VERSION 5.7 ;
  NOWIREEXTENSIONATPIN ON ;
  DIVIDERCHAR "/" ;
  BUSBITCHARS "[]" ;
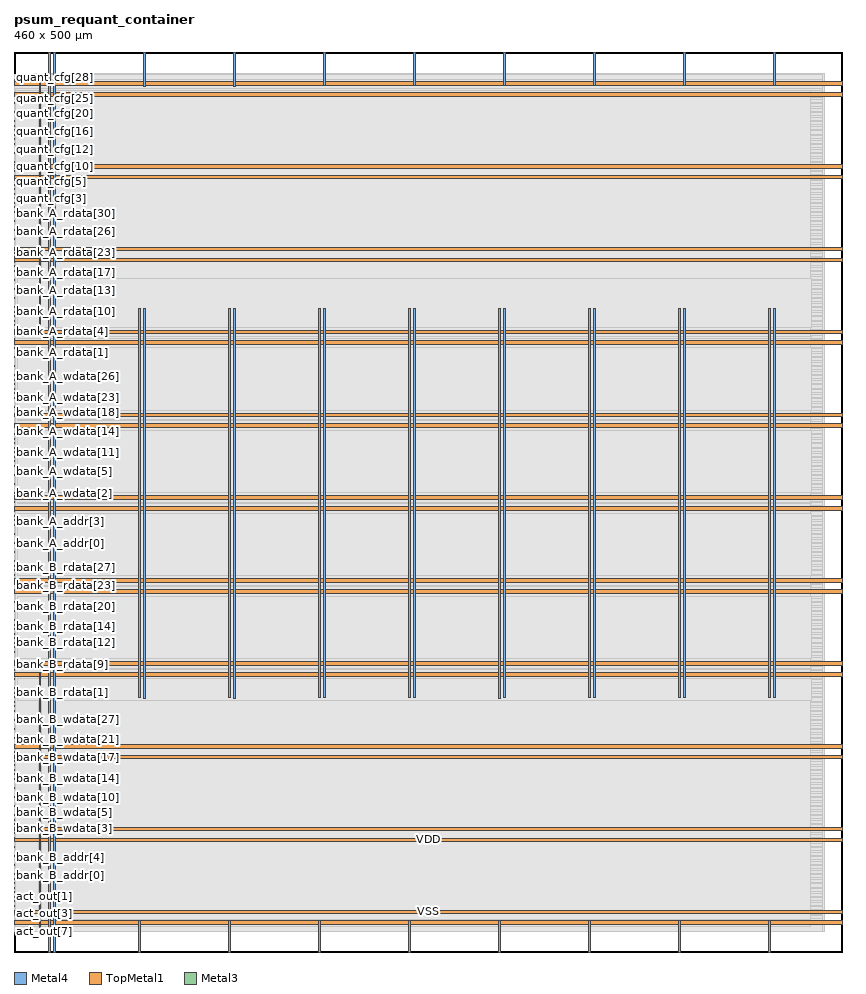
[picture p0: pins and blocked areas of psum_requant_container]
MACRO psum_requant_container
  CLASS BLOCK ;
  FOREIGN psum_requant_container ;
  ORIGIN 0.000 0.000 ;
  SIZE 460.000 BY 500.000 ;
  PIN VDD
    DIRECTION INOUT ;
    USE POWER ;
    PORT
      LAYER Metal4 ;
        RECT 19.100 0.000 20.100 500.000 ;
    END
    PORT
      LAYER Metal4 ;
        RECT 69.100 0.000 70.100 17.520 ;
    END
    PORT
      LAYER Metal4 ;
        RECT 69.100 141.260 70.100 357.520 ;
    END
    PORT
      LAYER Metal4 ;
        RECT 119.100 0.000 120.100 17.520 ;
    END
    PORT
      LAYER Metal4 ;
        RECT 119.100 141.260 120.100 357.520 ;
    END
    PORT
      LAYER Metal4 ;
        RECT 169.100 0.000 170.100 17.520 ;
    END
    PORT
      LAYER Metal4 ;
        RECT 169.100 141.260 170.100 357.520 ;
    END
    PORT
      LAYER Metal4 ;
        RECT 219.100 0.000 220.100 17.520 ;
    END
    PORT
      LAYER Metal4 ;
        RECT 219.100 141.260 220.100 357.520 ;
    END
    PORT
      LAYER Metal4 ;
        RECT 269.100 0.000 270.100 17.760 ;
    END
    PORT
      LAYER Metal4 ;
        RECT 269.100 141.020 270.100 357.760 ;
    END
    PORT
      LAYER Metal4 ;
        RECT 319.100 0.000 320.100 17.520 ;
    END
    PORT
      LAYER Metal4 ;
        RECT 319.100 141.260 320.100 357.520 ;
    END
    PORT
      LAYER Metal4 ;
        RECT 369.100 0.000 370.100 17.520 ;
    END
    PORT
      LAYER Metal4 ;
        RECT 369.100 141.260 370.100 357.520 ;
    END
    PORT
      LAYER Metal4 ;
        RECT 419.100 0.000 420.100 17.520 ;
    END
    PORT
      LAYER Metal4 ;
        RECT 419.100 141.260 420.100 357.520 ;
    END
    PORT
      LAYER TopMetal1 ;
        RECT 0.000 15.240 460.000 17.240 ;
    END
    PORT
      LAYER TopMetal1 ;
        RECT 0.000 61.270 460.000 63.270 ;
    END
    PORT
      LAYER TopMetal1 ;
        RECT 0.000 107.300 460.000 109.300 ;
    END
    PORT
      LAYER TopMetal1 ;
        RECT 0.000 153.330 460.000 155.330 ;
    END
    PORT
      LAYER TopMetal1 ;
        RECT 0.000 199.360 460.000 201.360 ;
    END
    PORT
      LAYER TopMetal1 ;
        RECT 0.000 245.390 460.000 247.390 ;
    END
    PORT
      LAYER TopMetal1 ;
        RECT 0.000 291.420 460.000 293.420 ;
    END
    PORT
      LAYER TopMetal1 ;
        RECT 0.000 337.450 460.000 339.450 ;
    END
    PORT
      LAYER TopMetal1 ;
        RECT 0.000 383.480 460.000 385.480 ;
    END
    PORT
      LAYER TopMetal1 ;
        RECT 0.000 429.510 460.000 431.510 ;
    END
    PORT
      LAYER TopMetal1 ;
        RECT 0.000 475.540 460.000 477.540 ;
    END
  END VDD
  PIN VSS
    DIRECTION INOUT ;
    USE GROUND ;
    PORT
      LAYER Metal4 ;
        RECT 22.100 0.000 23.100 500.000 ;
    END
    PORT
      LAYER Metal4 ;
        RECT 72.100 141.020 73.100 357.760 ;
    END
    PORT
      LAYER Metal4 ;
        RECT 72.100 481.020 73.100 500.000 ;
    END
    PORT
      LAYER Metal4 ;
        RECT 122.100 141.020 123.100 357.760 ;
    END
    PORT
      LAYER Metal4 ;
        RECT 122.100 481.020 123.100 500.000 ;
    END
    PORT
      LAYER Metal4 ;
        RECT 172.100 141.260 173.100 357.520 ;
    END
    PORT
      LAYER Metal4 ;
        RECT 172.100 481.260 173.100 500.000 ;
    END
    PORT
      LAYER Metal4 ;
        RECT 222.100 141.260 223.100 357.520 ;
    END
    PORT
      LAYER Metal4 ;
        RECT 222.100 481.260 223.100 500.000 ;
    END
    PORT
      LAYER Metal4 ;
        RECT 272.100 141.260 273.100 357.520 ;
    END
    PORT
      LAYER Metal4 ;
        RECT 272.100 481.260 273.100 500.000 ;
    END
    PORT
      LAYER Metal4 ;
        RECT 322.100 141.260 323.100 357.520 ;
    END
    PORT
      LAYER Metal4 ;
        RECT 322.100 481.260 323.100 500.000 ;
    END
    PORT
      LAYER Metal4 ;
        RECT 372.100 141.260 373.100 357.520 ;
    END
    PORT
      LAYER Metal4 ;
        RECT 372.100 481.260 373.100 500.000 ;
    END
    PORT
      LAYER Metal4 ;
        RECT 422.100 141.260 423.100 357.520 ;
    END
    PORT
      LAYER Metal4 ;
        RECT 422.100 481.260 423.100 500.000 ;
    END
    PORT
      LAYER TopMetal1 ;
        RECT 0.000 21.240 460.000 23.240 ;
    END
    PORT
      LAYER TopMetal1 ;
        RECT 0.000 67.270 460.000 69.270 ;
    END
    PORT
      LAYER TopMetal1 ;
        RECT 0.000 113.300 460.000 115.300 ;
    END
    PORT
      LAYER TopMetal1 ;
        RECT 0.000 159.330 460.000 161.330 ;
    END
    PORT
      LAYER TopMetal1 ;
        RECT 0.000 205.360 460.000 207.360 ;
    END
    PORT
      LAYER TopMetal1 ;
        RECT 0.000 251.390 460.000 253.390 ;
    END
    PORT
      LAYER TopMetal1 ;
        RECT 0.000 297.420 460.000 299.420 ;
    END
    PORT
      LAYER TopMetal1 ;
        RECT 0.000 343.450 460.000 345.450 ;
    END
    PORT
      LAYER TopMetal1 ;
        RECT 0.000 389.480 460.000 391.480 ;
    END
    PORT
      LAYER TopMetal1 ;
        RECT 0.000 435.510 460.000 437.510 ;
    END
    PORT
      LAYER TopMetal1 ;
        RECT 0.000 481.540 460.000 483.540 ;
    END
    PORT
      LAYER Metal4 ;
        RECT 13.900 11.120 14.900 155.200 ;
    END
    PORT
      LAYER Metal4 ;
        RECT 13.900 343.760 14.900 487.840 ;
    END
  END VSS
  PIN act_out[0]
    DIRECTION OUTPUT ;
    USE SIGNAL ;
    ANTENNADIFFAREA 0.708600 ;
    PORT
      LAYER Metal3 ;
        RECT 0.000 32.980 0.400 33.380 ;
    END
  END act_out[0]
  PIN act_out[1]
    DIRECTION OUTPUT ;
    USE SIGNAL ;
    ANTENNADIFFAREA 0.708600 ;
    PORT
      LAYER Metal3 ;
        RECT 0.000 30.460 0.400 30.860 ;
    END
  END act_out[1]
  PIN act_out[2]
    DIRECTION OUTPUT ;
    USE SIGNAL ;
    ANTENNADIFFAREA 0.708600 ;
    PORT
      LAYER Metal3 ;
        RECT 0.000 27.940 0.400 28.340 ;
    END
  END act_out[2]
  PIN act_out[3]
    DIRECTION OUTPUT ;
    USE SIGNAL ;
    ANTENNADIFFAREA 0.708600 ;
    PORT
      LAYER Metal3 ;
        RECT 0.000 25.420 0.400 25.820 ;
    END
  END act_out[3]
  PIN act_out[4]
    DIRECTION OUTPUT ;
    USE SIGNAL ;
    ANTENNADIFFAREA 0.708600 ;
    PORT
      LAYER Metal3 ;
        RECT 0.000 22.900 0.400 23.300 ;
    END
  END act_out[4]
  PIN act_out[5]
    DIRECTION OUTPUT ;
    USE SIGNAL ;
    ANTENNADIFFAREA 0.708600 ;
    PORT
      LAYER Metal3 ;
        RECT 0.000 20.380 0.400 20.780 ;
    END
  END act_out[5]
  PIN act_out[6]
    DIRECTION OUTPUT ;
    USE SIGNAL ;
    ANTENNADIFFAREA 0.708600 ;
    PORT
      LAYER Metal3 ;
        RECT 0.000 17.860 0.400 18.260 ;
    END
  END act_out[6]
  PIN act_out[7]
    DIRECTION OUTPUT ;
    USE SIGNAL ;
    ANTENNADIFFAREA 0.708600 ;
    PORT
      LAYER Metal3 ;
        RECT 0.000 15.340 0.400 15.740 ;
    END
  END act_out[7]
  PIN bank_A_addr[0]
    DIRECTION INPUT ;
    USE SIGNAL ;
    ANTENNAGATEAREA 0.180700 ;
    PORT
      LAYER Metal3 ;
        RECT 0.000 227.020 0.400 227.420 ;
    END
  END bank_A_addr[0]
  PIN bank_A_addr[1]
    DIRECTION INPUT ;
    USE SIGNAL ;
    ANTENNAGATEAREA 0.180700 ;
    PORT
      LAYER Metal3 ;
        RECT 0.000 229.540 0.400 229.940 ;
    END
  END bank_A_addr[1]
  PIN bank_A_addr[2]
    DIRECTION INPUT ;
    USE SIGNAL ;
    ANTENNAGATEAREA 0.180700 ;
    PORT
      LAYER Metal3 ;
        RECT 0.000 232.060 0.400 232.460 ;
    END
  END bank_A_addr[2]
  PIN bank_A_addr[3]
    DIRECTION INPUT ;
    USE SIGNAL ;
    ANTENNAGATEAREA 0.180700 ;
    PORT
      LAYER Metal3 ;
        RECT 0.000 234.580 0.400 234.980 ;
    END
  END bank_A_addr[3]
  PIN bank_A_addr[4]
    DIRECTION INPUT ;
    USE SIGNAL ;
    ANTENNAGATEAREA 0.180700 ;
    PORT
      LAYER Metal3 ;
        RECT 0.000 237.100 0.400 237.500 ;
    END
  END bank_A_addr[4]
  PIN bank_A_addr[5]
    DIRECTION INPUT ;
    USE SIGNAL ;
    ANTENNAGATEAREA 0.180700 ;
    PORT
      LAYER Metal3 ;
        RECT 0.000 239.620 0.400 240.020 ;
    END
  END bank_A_addr[5]
  PIN bank_A_addr[6]
    DIRECTION INPUT ;
    USE SIGNAL ;
    ANTENNAGATEAREA 0.180700 ;
    PORT
      LAYER Metal3 ;
        RECT 0.000 242.140 0.400 242.540 ;
    END
  END bank_A_addr[6]
  PIN bank_A_addr[7]
    DIRECTION INPUT ;
    USE SIGNAL ;
    ANTENNAGATEAREA 0.180700 ;
    PORT
      LAYER Metal3 ;
        RECT 0.000 244.660 0.400 245.060 ;
    END
  END bank_A_addr[7]
  PIN bank_A_rdata[0]
    DIRECTION OUTPUT ;
    USE SIGNAL ;
    ANTENNADIFFAREA 0.708600 ;
    PORT
      LAYER Metal3 ;
        RECT 0.000 330.340 0.400 330.740 ;
    END
  END bank_A_rdata[0]
  PIN bank_A_rdata[10]
    DIRECTION OUTPUT ;
    USE SIGNAL ;
    ANTENNADIFFAREA 0.708600 ;
    PORT
      LAYER Metal3 ;
        RECT 0.000 355.540 0.400 355.940 ;
    END
  END bank_A_rdata[10]
  PIN bank_A_rdata[11]
    DIRECTION OUTPUT ;
    USE SIGNAL ;
    ANTENNADIFFAREA 0.708600 ;
    PORT
      LAYER Metal3 ;
        RECT 0.000 358.060 0.400 358.460 ;
    END
  END bank_A_rdata[11]
  PIN bank_A_rdata[12]
    DIRECTION OUTPUT ;
    USE SIGNAL ;
    ANTENNADIFFAREA 0.708600 ;
    PORT
      LAYER Metal3 ;
        RECT 0.000 360.580 0.400 360.980 ;
    END
  END bank_A_rdata[12]
  PIN bank_A_rdata[13]
    DIRECTION OUTPUT ;
    USE SIGNAL ;
    ANTENNADIFFAREA 0.708600 ;
    PORT
      LAYER Metal3 ;
        RECT 0.000 363.100 0.400 363.500 ;
    END
  END bank_A_rdata[13]
  PIN bank_A_rdata[14]
    DIRECTION OUTPUT ;
    USE SIGNAL ;
    ANTENNADIFFAREA 0.708600 ;
    PORT
      LAYER Metal3 ;
        RECT 0.000 365.620 0.400 366.020 ;
    END
  END bank_A_rdata[14]
  PIN bank_A_rdata[15]
    DIRECTION OUTPUT ;
    USE SIGNAL ;
    ANTENNADIFFAREA 0.708600 ;
    PORT
      LAYER Metal3 ;
        RECT 0.000 368.140 0.400 368.540 ;
    END
  END bank_A_rdata[15]
  PIN bank_A_rdata[16]
    DIRECTION OUTPUT ;
    USE SIGNAL ;
    ANTENNADIFFAREA 0.708600 ;
    PORT
      LAYER Metal3 ;
        RECT 0.000 370.660 0.400 371.060 ;
    END
  END bank_A_rdata[16]
  PIN bank_A_rdata[17]
    DIRECTION OUTPUT ;
    USE SIGNAL ;
    ANTENNADIFFAREA 0.708600 ;
    PORT
      LAYER Metal3 ;
        RECT 0.000 373.180 0.400 373.580 ;
    END
  END bank_A_rdata[17]
  PIN bank_A_rdata[18]
    DIRECTION OUTPUT ;
    USE SIGNAL ;
    ANTENNADIFFAREA 0.708600 ;
    PORT
      LAYER Metal3 ;
        RECT 0.000 375.700 0.400 376.100 ;
    END
  END bank_A_rdata[18]
  PIN bank_A_rdata[19]
    DIRECTION OUTPUT ;
    USE SIGNAL ;
    ANTENNADIFFAREA 0.708600 ;
    PORT
      LAYER Metal3 ;
        RECT 0.000 378.220 0.400 378.620 ;
    END
  END bank_A_rdata[19]
  PIN bank_A_rdata[1]
    DIRECTION OUTPUT ;
    USE SIGNAL ;
    ANTENNADIFFAREA 0.708600 ;
    PORT
      LAYER Metal3 ;
        RECT 0.000 332.860 0.400 333.260 ;
    END
  END bank_A_rdata[1]
  PIN bank_A_rdata[20]
    DIRECTION OUTPUT ;
    USE SIGNAL ;
    ANTENNADIFFAREA 0.708600 ;
    PORT
      LAYER Metal3 ;
        RECT 0.000 380.740 0.400 381.140 ;
    END
  END bank_A_rdata[20]
  PIN bank_A_rdata[21]
    DIRECTION OUTPUT ;
    USE SIGNAL ;
    ANTENNADIFFAREA 0.708600 ;
    PORT
      LAYER Metal3 ;
        RECT 0.000 383.260 0.400 383.660 ;
    END
  END bank_A_rdata[21]
  PIN bank_A_rdata[22]
    DIRECTION OUTPUT ;
    USE SIGNAL ;
    ANTENNADIFFAREA 0.708600 ;
    PORT
      LAYER Metal3 ;
        RECT 0.000 385.780 0.400 386.180 ;
    END
  END bank_A_rdata[22]
  PIN bank_A_rdata[23]
    DIRECTION OUTPUT ;
    USE SIGNAL ;
    ANTENNADIFFAREA 0.708600 ;
    PORT
      LAYER Metal3 ;
        RECT 0.000 388.300 0.400 388.700 ;
    END
  END bank_A_rdata[23]
  PIN bank_A_rdata[24]
    DIRECTION OUTPUT ;
    USE SIGNAL ;
    ANTENNADIFFAREA 0.708600 ;
    PORT
      LAYER Metal3 ;
        RECT 0.000 390.820 0.400 391.220 ;
    END
  END bank_A_rdata[24]
  PIN bank_A_rdata[25]
    DIRECTION OUTPUT ;
    USE SIGNAL ;
    ANTENNADIFFAREA 0.708600 ;
    PORT
      LAYER Metal3 ;
        RECT 0.000 393.340 0.400 393.740 ;
    END
  END bank_A_rdata[25]
  PIN bank_A_rdata[26]
    DIRECTION OUTPUT ;
    USE SIGNAL ;
    ANTENNADIFFAREA 0.708600 ;
    PORT
      LAYER Metal3 ;
        RECT 0.000 395.860 0.400 396.260 ;
    END
  END bank_A_rdata[26]
  PIN bank_A_rdata[27]
    DIRECTION OUTPUT ;
    USE SIGNAL ;
    ANTENNADIFFAREA 0.708600 ;
    PORT
      LAYER Metal3 ;
        RECT 0.000 398.380 0.400 398.780 ;
    END
  END bank_A_rdata[27]
  PIN bank_A_rdata[28]
    DIRECTION OUTPUT ;
    USE SIGNAL ;
    ANTENNADIFFAREA 0.708600 ;
    PORT
      LAYER Metal3 ;
        RECT 0.000 400.900 0.400 401.300 ;
    END
  END bank_A_rdata[28]
  PIN bank_A_rdata[29]
    DIRECTION OUTPUT ;
    USE SIGNAL ;
    ANTENNADIFFAREA 0.708600 ;
    PORT
      LAYER Metal3 ;
        RECT 0.000 403.420 0.400 403.820 ;
    END
  END bank_A_rdata[29]
  PIN bank_A_rdata[2]
    DIRECTION OUTPUT ;
    USE SIGNAL ;
    ANTENNADIFFAREA 0.708600 ;
    PORT
      LAYER Metal3 ;
        RECT 0.000 335.380 0.400 335.780 ;
    END
  END bank_A_rdata[2]
  PIN bank_A_rdata[30]
    DIRECTION OUTPUT ;
    USE SIGNAL ;
    ANTENNADIFFAREA 0.708600 ;
    PORT
      LAYER Metal3 ;
        RECT 0.000 405.940 0.400 406.340 ;
    END
  END bank_A_rdata[30]
  PIN bank_A_rdata[31]
    DIRECTION OUTPUT ;
    USE SIGNAL ;
    ANTENNADIFFAREA 0.708600 ;
    PORT
      LAYER Metal3 ;
        RECT 0.000 408.460 0.400 408.860 ;
    END
  END bank_A_rdata[31]
  PIN bank_A_rdata[3]
    DIRECTION OUTPUT ;
    USE SIGNAL ;
    ANTENNADIFFAREA 0.708600 ;
    PORT
      LAYER Metal3 ;
        RECT 0.000 337.900 0.400 338.300 ;
    END
  END bank_A_rdata[3]
  PIN bank_A_rdata[4]
    DIRECTION OUTPUT ;
    USE SIGNAL ;
    ANTENNADIFFAREA 0.708600 ;
    PORT
      LAYER Metal3 ;
        RECT 0.000 340.420 0.400 340.820 ;
    END
  END bank_A_rdata[4]
  PIN bank_A_rdata[5]
    DIRECTION OUTPUT ;
    USE SIGNAL ;
    ANTENNADIFFAREA 0.708600 ;
    PORT
      LAYER Metal3 ;
        RECT 0.000 342.940 0.400 343.340 ;
    END
  END bank_A_rdata[5]
  PIN bank_A_rdata[6]
    DIRECTION OUTPUT ;
    USE SIGNAL ;
    ANTENNADIFFAREA 0.708600 ;
    PORT
      LAYER Metal3 ;
        RECT 0.000 345.460 0.400 345.860 ;
    END
  END bank_A_rdata[6]
  PIN bank_A_rdata[7]
    DIRECTION OUTPUT ;
    USE SIGNAL ;
    ANTENNADIFFAREA 0.708600 ;
    PORT
      LAYER Metal3 ;
        RECT 0.000 347.980 0.400 348.380 ;
    END
  END bank_A_rdata[7]
  PIN bank_A_rdata[8]
    DIRECTION OUTPUT ;
    USE SIGNAL ;
    ANTENNADIFFAREA 0.708600 ;
    PORT
      LAYER Metal3 ;
        RECT 0.000 350.500 0.400 350.900 ;
    END
  END bank_A_rdata[8]
  PIN bank_A_rdata[9]
    DIRECTION OUTPUT ;
    USE SIGNAL ;
    ANTENNADIFFAREA 0.708600 ;
    PORT
      LAYER Metal3 ;
        RECT 0.000 353.020 0.400 353.420 ;
    END
  END bank_A_rdata[9]
  PIN bank_A_wdata[0]
    DIRECTION INPUT ;
    USE SIGNAL ;
    ANTENNAGATEAREA 0.180700 ;
    PORT
      LAYER Metal3 ;
        RECT 0.000 249.700 0.400 250.100 ;
    END
  END bank_A_wdata[0]
  PIN bank_A_wdata[10]
    DIRECTION INPUT ;
    USE SIGNAL ;
    ANTENNAGATEAREA 0.180700 ;
    PORT
      LAYER Metal3 ;
        RECT 0.000 274.900 0.400 275.300 ;
    END
  END bank_A_wdata[10]
  PIN bank_A_wdata[11]
    DIRECTION INPUT ;
    USE SIGNAL ;
    ANTENNAGATEAREA 0.180700 ;
    PORT
      LAYER Metal3 ;
        RECT 0.000 277.420 0.400 277.820 ;
    END
  END bank_A_wdata[11]
  PIN bank_A_wdata[12]
    DIRECTION INPUT ;
    USE SIGNAL ;
    ANTENNAGATEAREA 0.180700 ;
    PORT
      LAYER Metal3 ;
        RECT 0.000 279.940 0.400 280.340 ;
    END
  END bank_A_wdata[12]
  PIN bank_A_wdata[13]
    DIRECTION INPUT ;
    USE SIGNAL ;
    ANTENNAGATEAREA 0.180700 ;
    PORT
      LAYER Metal3 ;
        RECT 0.000 282.460 0.400 282.860 ;
    END
  END bank_A_wdata[13]
  PIN bank_A_wdata[14]
    DIRECTION INPUT ;
    USE SIGNAL ;
    ANTENNAGATEAREA 0.180700 ;
    PORT
      LAYER Metal3 ;
        RECT 0.000 284.980 0.400 285.380 ;
    END
  END bank_A_wdata[14]
  PIN bank_A_wdata[15]
    DIRECTION INPUT ;
    USE SIGNAL ;
    ANTENNAGATEAREA 0.180700 ;
    PORT
      LAYER Metal3 ;
        RECT 0.000 287.500 0.400 287.900 ;
    END
  END bank_A_wdata[15]
  PIN bank_A_wdata[16]
    DIRECTION INPUT ;
    USE SIGNAL ;
    ANTENNAGATEAREA 0.180700 ;
    PORT
      LAYER Metal3 ;
        RECT 0.000 290.020 0.400 290.420 ;
    END
  END bank_A_wdata[16]
  PIN bank_A_wdata[17]
    DIRECTION INPUT ;
    USE SIGNAL ;
    ANTENNAGATEAREA 0.180700 ;
    PORT
      LAYER Metal3 ;
        RECT 0.000 292.540 0.400 292.940 ;
    END
  END bank_A_wdata[17]
  PIN bank_A_wdata[18]
    DIRECTION INPUT ;
    USE SIGNAL ;
    ANTENNAGATEAREA 0.180700 ;
    PORT
      LAYER Metal3 ;
        RECT 0.000 295.060 0.400 295.460 ;
    END
  END bank_A_wdata[18]
  PIN bank_A_wdata[19]
    DIRECTION INPUT ;
    USE SIGNAL ;
    ANTENNAGATEAREA 0.180700 ;
    PORT
      LAYER Metal3 ;
        RECT 0.000 297.580 0.400 297.980 ;
    END
  END bank_A_wdata[19]
  PIN bank_A_wdata[1]
    DIRECTION INPUT ;
    USE SIGNAL ;
    ANTENNAGATEAREA 0.180700 ;
    PORT
      LAYER Metal3 ;
        RECT 0.000 252.220 0.400 252.620 ;
    END
  END bank_A_wdata[1]
  PIN bank_A_wdata[20]
    DIRECTION INPUT ;
    USE SIGNAL ;
    ANTENNAGATEAREA 0.180700 ;
    PORT
      LAYER Metal3 ;
        RECT 0.000 300.100 0.400 300.500 ;
    END
  END bank_A_wdata[20]
  PIN bank_A_wdata[21]
    DIRECTION INPUT ;
    USE SIGNAL ;
    ANTENNAGATEAREA 0.180700 ;
    PORT
      LAYER Metal3 ;
        RECT 0.000 302.620 0.400 303.020 ;
    END
  END bank_A_wdata[21]
  PIN bank_A_wdata[22]
    DIRECTION INPUT ;
    USE SIGNAL ;
    ANTENNAGATEAREA 0.180700 ;
    PORT
      LAYER Metal3 ;
        RECT 0.000 305.140 0.400 305.540 ;
    END
  END bank_A_wdata[22]
  PIN bank_A_wdata[23]
    DIRECTION INPUT ;
    USE SIGNAL ;
    ANTENNAGATEAREA 0.180700 ;
    PORT
      LAYER Metal3 ;
        RECT 0.000 307.660 0.400 308.060 ;
    END
  END bank_A_wdata[23]
  PIN bank_A_wdata[24]
    DIRECTION INPUT ;
    USE SIGNAL ;
    ANTENNAGATEAREA 0.180700 ;
    PORT
      LAYER Metal3 ;
        RECT 0.000 310.180 0.400 310.580 ;
    END
  END bank_A_wdata[24]
  PIN bank_A_wdata[25]
    DIRECTION INPUT ;
    USE SIGNAL ;
    ANTENNAGATEAREA 0.180700 ;
    PORT
      LAYER Metal3 ;
        RECT 0.000 312.700 0.400 313.100 ;
    END
  END bank_A_wdata[25]
  PIN bank_A_wdata[26]
    DIRECTION INPUT ;
    USE SIGNAL ;
    ANTENNAGATEAREA 0.180700 ;
    PORT
      LAYER Metal3 ;
        RECT 0.000 315.220 0.400 315.620 ;
    END
  END bank_A_wdata[26]
  PIN bank_A_wdata[27]
    DIRECTION INPUT ;
    USE SIGNAL ;
    ANTENNAGATEAREA 0.180700 ;
    PORT
      LAYER Metal3 ;
        RECT 0.000 317.740 0.400 318.140 ;
    END
  END bank_A_wdata[27]
  PIN bank_A_wdata[28]
    DIRECTION INPUT ;
    USE SIGNAL ;
    ANTENNAGATEAREA 0.180700 ;
    PORT
      LAYER Metal3 ;
        RECT 0.000 320.260 0.400 320.660 ;
    END
  END bank_A_wdata[28]
  PIN bank_A_wdata[29]
    DIRECTION INPUT ;
    USE SIGNAL ;
    ANTENNAGATEAREA 0.180700 ;
    PORT
      LAYER Metal3 ;
        RECT 0.000 322.780 0.400 323.180 ;
    END
  END bank_A_wdata[29]
  PIN bank_A_wdata[2]
    DIRECTION INPUT ;
    USE SIGNAL ;
    ANTENNAGATEAREA 0.180700 ;
    PORT
      LAYER Metal3 ;
        RECT 0.000 254.740 0.400 255.140 ;
    END
  END bank_A_wdata[2]
  PIN bank_A_wdata[30]
    DIRECTION INPUT ;
    USE SIGNAL ;
    ANTENNAGATEAREA 0.180700 ;
    PORT
      LAYER Metal3 ;
        RECT 0.000 325.300 0.400 325.700 ;
    END
  END bank_A_wdata[30]
  PIN bank_A_wdata[31]
    DIRECTION INPUT ;
    USE SIGNAL ;
    ANTENNAGATEAREA 0.180700 ;
    PORT
      LAYER Metal3 ;
        RECT 0.000 327.820 0.400 328.220 ;
    END
  END bank_A_wdata[31]
  PIN bank_A_wdata[3]
    DIRECTION INPUT ;
    USE SIGNAL ;
    ANTENNAGATEAREA 0.180700 ;
    PORT
      LAYER Metal3 ;
        RECT 0.000 257.260 0.400 257.660 ;
    END
  END bank_A_wdata[3]
  PIN bank_A_wdata[4]
    DIRECTION INPUT ;
    USE SIGNAL ;
    ANTENNAGATEAREA 0.180700 ;
    PORT
      LAYER Metal3 ;
        RECT 0.000 259.780 0.400 260.180 ;
    END
  END bank_A_wdata[4]
  PIN bank_A_wdata[5]
    DIRECTION INPUT ;
    USE SIGNAL ;
    ANTENNAGATEAREA 0.180700 ;
    PORT
      LAYER Metal3 ;
        RECT 0.000 262.300 0.400 262.700 ;
    END
  END bank_A_wdata[5]
  PIN bank_A_wdata[6]
    DIRECTION INPUT ;
    USE SIGNAL ;
    ANTENNAGATEAREA 0.180700 ;
    PORT
      LAYER Metal3 ;
        RECT 0.000 264.820 0.400 265.220 ;
    END
  END bank_A_wdata[6]
  PIN bank_A_wdata[7]
    DIRECTION INPUT ;
    USE SIGNAL ;
    ANTENNAGATEAREA 0.180700 ;
    PORT
      LAYER Metal3 ;
        RECT 0.000 267.340 0.400 267.740 ;
    END
  END bank_A_wdata[7]
  PIN bank_A_wdata[8]
    DIRECTION INPUT ;
    USE SIGNAL ;
    ANTENNAGATEAREA 0.180700 ;
    PORT
      LAYER Metal3 ;
        RECT 0.000 269.860 0.400 270.260 ;
    END
  END bank_A_wdata[8]
  PIN bank_A_wdata[9]
    DIRECTION INPUT ;
    USE SIGNAL ;
    ANTENNAGATEAREA 0.180700 ;
    PORT
      LAYER Metal3 ;
        RECT 0.000 272.380 0.400 272.780 ;
    END
  END bank_A_wdata[9]
  PIN bank_A_we
    DIRECTION INPUT ;
    USE SIGNAL ;
    ANTENNAGATEAREA 0.180700 ;
    PORT
      LAYER Metal3 ;
        RECT 0.000 247.180 0.400 247.580 ;
    END
  END bank_A_we
  PIN bank_B_addr[0]
    DIRECTION INPUT ;
    USE SIGNAL ;
    ANTENNAGATEAREA 0.180700 ;
    PORT
      LAYER Metal3 ;
        RECT 0.000 38.020 0.400 38.420 ;
    END
  END bank_B_addr[0]
  PIN bank_B_addr[1]
    DIRECTION INPUT ;
    USE SIGNAL ;
    ANTENNAGATEAREA 0.180700 ;
    PORT
      LAYER Metal3 ;
        RECT 0.000 40.540 0.400 40.940 ;
    END
  END bank_B_addr[1]
  PIN bank_B_addr[2]
    DIRECTION INPUT ;
    USE SIGNAL ;
    ANTENNAGATEAREA 0.180700 ;
    PORT
      LAYER Metal3 ;
        RECT 0.000 43.060 0.400 43.460 ;
    END
  END bank_B_addr[2]
  PIN bank_B_addr[3]
    DIRECTION INPUT ;
    USE SIGNAL ;
    ANTENNAGATEAREA 0.180700 ;
    PORT
      LAYER Metal3 ;
        RECT 0.000 45.580 0.400 45.980 ;
    END
  END bank_B_addr[3]
  PIN bank_B_addr[4]
    DIRECTION INPUT ;
    USE SIGNAL ;
    ANTENNAGATEAREA 0.180700 ;
    PORT
      LAYER Metal3 ;
        RECT 0.000 48.100 0.400 48.500 ;
    END
  END bank_B_addr[4]
  PIN bank_B_addr[5]
    DIRECTION INPUT ;
    USE SIGNAL ;
    ANTENNAGATEAREA 0.180700 ;
    PORT
      LAYER Metal3 ;
        RECT 0.000 50.620 0.400 51.020 ;
    END
  END bank_B_addr[5]
  PIN bank_B_addr[6]
    DIRECTION INPUT ;
    USE SIGNAL ;
    ANTENNAGATEAREA 0.180700 ;
    PORT
      LAYER Metal3 ;
        RECT 0.000 53.140 0.400 53.540 ;
    END
  END bank_B_addr[6]
  PIN bank_B_addr[7]
    DIRECTION INPUT ;
    USE SIGNAL ;
    ANTENNAGATEAREA 0.180700 ;
    PORT
      LAYER Metal3 ;
        RECT 0.000 55.660 0.400 56.060 ;
    END
  END bank_B_addr[7]
  PIN bank_B_rdata[0]
    DIRECTION OUTPUT ;
    USE SIGNAL ;
    ANTENNADIFFAREA 0.708600 ;
    PORT
      LAYER Metal3 ;
        RECT 0.000 141.340 0.400 141.740 ;
    END
  END bank_B_rdata[0]
  PIN bank_B_rdata[10]
    DIRECTION OUTPUT ;
    USE SIGNAL ;
    ANTENNADIFFAREA 0.708600 ;
    PORT
      LAYER Metal3 ;
        RECT 0.000 166.540 0.400 166.940 ;
    END
  END bank_B_rdata[10]
  PIN bank_B_rdata[11]
    DIRECTION OUTPUT ;
    USE SIGNAL ;
    ANTENNADIFFAREA 0.708600 ;
    PORT
      LAYER Metal3 ;
        RECT 0.000 169.060 0.400 169.460 ;
    END
  END bank_B_rdata[11]
  PIN bank_B_rdata[12]
    DIRECTION OUTPUT ;
    USE SIGNAL ;
    ANTENNADIFFAREA 0.708600 ;
    PORT
      LAYER Metal3 ;
        RECT 0.000 171.580 0.400 171.980 ;
    END
  END bank_B_rdata[12]
  PIN bank_B_rdata[13]
    DIRECTION OUTPUT ;
    USE SIGNAL ;
    ANTENNADIFFAREA 0.708600 ;
    PORT
      LAYER Metal3 ;
        RECT 0.000 174.100 0.400 174.500 ;
    END
  END bank_B_rdata[13]
  PIN bank_B_rdata[14]
    DIRECTION OUTPUT ;
    USE SIGNAL ;
    ANTENNADIFFAREA 0.708600 ;
    PORT
      LAYER Metal3 ;
        RECT 0.000 176.620 0.400 177.020 ;
    END
  END bank_B_rdata[14]
  PIN bank_B_rdata[15]
    DIRECTION OUTPUT ;
    USE SIGNAL ;
    ANTENNADIFFAREA 0.708600 ;
    PORT
      LAYER Metal3 ;
        RECT 0.000 179.140 0.400 179.540 ;
    END
  END bank_B_rdata[15]
  PIN bank_B_rdata[16]
    DIRECTION OUTPUT ;
    USE SIGNAL ;
    ANTENNADIFFAREA 0.708600 ;
    PORT
      LAYER Metal3 ;
        RECT 0.000 181.660 0.400 182.060 ;
    END
  END bank_B_rdata[16]
  PIN bank_B_rdata[17]
    DIRECTION OUTPUT ;
    USE SIGNAL ;
    ANTENNADIFFAREA 0.708600 ;
    PORT
      LAYER Metal3 ;
        RECT 0.000 184.180 0.400 184.580 ;
    END
  END bank_B_rdata[17]
  PIN bank_B_rdata[18]
    DIRECTION OUTPUT ;
    USE SIGNAL ;
    ANTENNADIFFAREA 0.708600 ;
    PORT
      LAYER Metal3 ;
        RECT 0.000 186.700 0.400 187.100 ;
    END
  END bank_B_rdata[18]
  PIN bank_B_rdata[19]
    DIRECTION OUTPUT ;
    USE SIGNAL ;
    ANTENNADIFFAREA 0.708600 ;
    PORT
      LAYER Metal3 ;
        RECT 0.000 189.220 0.400 189.620 ;
    END
  END bank_B_rdata[19]
  PIN bank_B_rdata[1]
    DIRECTION OUTPUT ;
    USE SIGNAL ;
    ANTENNADIFFAREA 0.708600 ;
    PORT
      LAYER Metal3 ;
        RECT 0.000 143.860 0.400 144.260 ;
    END
  END bank_B_rdata[1]
  PIN bank_B_rdata[20]
    DIRECTION OUTPUT ;
    USE SIGNAL ;
    ANTENNADIFFAREA 0.708600 ;
    PORT
      LAYER Metal3 ;
        RECT 0.000 191.740 0.400 192.140 ;
    END
  END bank_B_rdata[20]
  PIN bank_B_rdata[21]
    DIRECTION OUTPUT ;
    USE SIGNAL ;
    ANTENNADIFFAREA 0.708600 ;
    PORT
      LAYER Metal3 ;
        RECT 0.000 194.260 0.400 194.660 ;
    END
  END bank_B_rdata[21]
  PIN bank_B_rdata[22]
    DIRECTION OUTPUT ;
    USE SIGNAL ;
    ANTENNADIFFAREA 0.708600 ;
    PORT
      LAYER Metal3 ;
        RECT 0.000 196.780 0.400 197.180 ;
    END
  END bank_B_rdata[22]
  PIN bank_B_rdata[23]
    DIRECTION OUTPUT ;
    USE SIGNAL ;
    ANTENNADIFFAREA 0.708600 ;
    PORT
      LAYER Metal3 ;
        RECT 0.000 199.300 0.400 199.700 ;
    END
  END bank_B_rdata[23]
  PIN bank_B_rdata[24]
    DIRECTION OUTPUT ;
    USE SIGNAL ;
    ANTENNADIFFAREA 0.708600 ;
    PORT
      LAYER Metal3 ;
        RECT 0.000 201.820 0.400 202.220 ;
    END
  END bank_B_rdata[24]
  PIN bank_B_rdata[25]
    DIRECTION OUTPUT ;
    USE SIGNAL ;
    ANTENNADIFFAREA 0.708600 ;
    PORT
      LAYER Metal3 ;
        RECT 0.000 204.340 0.400 204.740 ;
    END
  END bank_B_rdata[25]
  PIN bank_B_rdata[26]
    DIRECTION OUTPUT ;
    USE SIGNAL ;
    ANTENNADIFFAREA 0.708600 ;
    PORT
      LAYER Metal3 ;
        RECT 0.000 206.860 0.400 207.260 ;
    END
  END bank_B_rdata[26]
  PIN bank_B_rdata[27]
    DIRECTION OUTPUT ;
    USE SIGNAL ;
    ANTENNADIFFAREA 0.708600 ;
    PORT
      LAYER Metal3 ;
        RECT 0.000 209.380 0.400 209.780 ;
    END
  END bank_B_rdata[27]
  PIN bank_B_rdata[28]
    DIRECTION OUTPUT ;
    USE SIGNAL ;
    ANTENNADIFFAREA 0.708600 ;
    PORT
      LAYER Metal3 ;
        RECT 0.000 211.900 0.400 212.300 ;
    END
  END bank_B_rdata[28]
  PIN bank_B_rdata[29]
    DIRECTION OUTPUT ;
    USE SIGNAL ;
    ANTENNADIFFAREA 0.708600 ;
    PORT
      LAYER Metal3 ;
        RECT 0.000 214.420 0.400 214.820 ;
    END
  END bank_B_rdata[29]
  PIN bank_B_rdata[2]
    DIRECTION OUTPUT ;
    USE SIGNAL ;
    ANTENNADIFFAREA 0.708600 ;
    PORT
      LAYER Metal3 ;
        RECT 0.000 146.380 0.400 146.780 ;
    END
  END bank_B_rdata[2]
  PIN bank_B_rdata[30]
    DIRECTION OUTPUT ;
    USE SIGNAL ;
    ANTENNADIFFAREA 0.708600 ;
    PORT
      LAYER Metal3 ;
        RECT 0.000 216.940 0.400 217.340 ;
    END
  END bank_B_rdata[30]
  PIN bank_B_rdata[31]
    DIRECTION OUTPUT ;
    USE SIGNAL ;
    ANTENNADIFFAREA 0.708600 ;
    PORT
      LAYER Metal3 ;
        RECT 0.000 219.460 0.400 219.860 ;
    END
  END bank_B_rdata[31]
  PIN bank_B_rdata[3]
    DIRECTION OUTPUT ;
    USE SIGNAL ;
    ANTENNADIFFAREA 0.708600 ;
    PORT
      LAYER Metal3 ;
        RECT 0.000 148.900 0.400 149.300 ;
    END
  END bank_B_rdata[3]
  PIN bank_B_rdata[4]
    DIRECTION OUTPUT ;
    USE SIGNAL ;
    ANTENNADIFFAREA 0.708600 ;
    PORT
      LAYER Metal3 ;
        RECT 0.000 151.420 0.400 151.820 ;
    END
  END bank_B_rdata[4]
  PIN bank_B_rdata[5]
    DIRECTION OUTPUT ;
    USE SIGNAL ;
    ANTENNADIFFAREA 0.708600 ;
    PORT
      LAYER Metal3 ;
        RECT 0.000 153.940 0.400 154.340 ;
    END
  END bank_B_rdata[5]
  PIN bank_B_rdata[6]
    DIRECTION OUTPUT ;
    USE SIGNAL ;
    ANTENNADIFFAREA 0.708600 ;
    PORT
      LAYER Metal3 ;
        RECT 0.000 156.460 0.400 156.860 ;
    END
  END bank_B_rdata[6]
  PIN bank_B_rdata[7]
    DIRECTION OUTPUT ;
    USE SIGNAL ;
    ANTENNADIFFAREA 0.708600 ;
    PORT
      LAYER Metal3 ;
        RECT 0.000 158.980 0.400 159.380 ;
    END
  END bank_B_rdata[7]
  PIN bank_B_rdata[8]
    DIRECTION OUTPUT ;
    USE SIGNAL ;
    ANTENNADIFFAREA 0.708600 ;
    PORT
      LAYER Metal3 ;
        RECT 0.000 161.500 0.400 161.900 ;
    END
  END bank_B_rdata[8]
  PIN bank_B_rdata[9]
    DIRECTION OUTPUT ;
    USE SIGNAL ;
    ANTENNADIFFAREA 0.708600 ;
    PORT
      LAYER Metal3 ;
        RECT 0.000 164.020 0.400 164.420 ;
    END
  END bank_B_rdata[9]
  PIN bank_B_wdata[0]
    DIRECTION INPUT ;
    USE SIGNAL ;
    ANTENNAGATEAREA 0.180700 ;
    PORT
      LAYER Metal3 ;
        RECT 0.000 60.700 0.400 61.100 ;
    END
  END bank_B_wdata[0]
  PIN bank_B_wdata[10]
    DIRECTION INPUT ;
    USE SIGNAL ;
    ANTENNAGATEAREA 0.180700 ;
    PORT
      LAYER Metal3 ;
        RECT 0.000 85.900 0.400 86.300 ;
    END
  END bank_B_wdata[10]
  PIN bank_B_wdata[11]
    DIRECTION INPUT ;
    USE SIGNAL ;
    ANTENNAGATEAREA 0.180700 ;
    PORT
      LAYER Metal3 ;
        RECT 0.000 88.420 0.400 88.820 ;
    END
  END bank_B_wdata[11]
  PIN bank_B_wdata[12]
    DIRECTION INPUT ;
    USE SIGNAL ;
    ANTENNAGATEAREA 0.180700 ;
    PORT
      LAYER Metal3 ;
        RECT 0.000 90.940 0.400 91.340 ;
    END
  END bank_B_wdata[12]
  PIN bank_B_wdata[13]
    DIRECTION INPUT ;
    USE SIGNAL ;
    ANTENNAGATEAREA 0.180700 ;
    PORT
      LAYER Metal3 ;
        RECT 0.000 93.460 0.400 93.860 ;
    END
  END bank_B_wdata[13]
  PIN bank_B_wdata[14]
    DIRECTION INPUT ;
    USE SIGNAL ;
    ANTENNAGATEAREA 0.180700 ;
    PORT
      LAYER Metal3 ;
        RECT 0.000 95.980 0.400 96.380 ;
    END
  END bank_B_wdata[14]
  PIN bank_B_wdata[15]
    DIRECTION INPUT ;
    USE SIGNAL ;
    ANTENNAGATEAREA 0.180700 ;
    PORT
      LAYER Metal3 ;
        RECT 0.000 98.500 0.400 98.900 ;
    END
  END bank_B_wdata[15]
  PIN bank_B_wdata[16]
    DIRECTION INPUT ;
    USE SIGNAL ;
    ANTENNAGATEAREA 0.180700 ;
    PORT
      LAYER Metal3 ;
        RECT 0.000 101.020 0.400 101.420 ;
    END
  END bank_B_wdata[16]
  PIN bank_B_wdata[17]
    DIRECTION INPUT ;
    USE SIGNAL ;
    ANTENNAGATEAREA 0.180700 ;
    PORT
      LAYER Metal3 ;
        RECT 0.000 103.540 0.400 103.940 ;
    END
  END bank_B_wdata[17]
  PIN bank_B_wdata[18]
    DIRECTION INPUT ;
    USE SIGNAL ;
    ANTENNAGATEAREA 0.180700 ;
    PORT
      LAYER Metal3 ;
        RECT 0.000 106.060 0.400 106.460 ;
    END
  END bank_B_wdata[18]
  PIN bank_B_wdata[19]
    DIRECTION INPUT ;
    USE SIGNAL ;
    ANTENNAGATEAREA 0.180700 ;
    PORT
      LAYER Metal3 ;
        RECT 0.000 108.580 0.400 108.980 ;
    END
  END bank_B_wdata[19]
  PIN bank_B_wdata[1]
    DIRECTION INPUT ;
    USE SIGNAL ;
    ANTENNAGATEAREA 0.180700 ;
    PORT
      LAYER Metal3 ;
        RECT 0.000 63.220 0.400 63.620 ;
    END
  END bank_B_wdata[1]
  PIN bank_B_wdata[20]
    DIRECTION INPUT ;
    USE SIGNAL ;
    ANTENNAGATEAREA 0.180700 ;
    PORT
      LAYER Metal3 ;
        RECT 0.000 111.100 0.400 111.500 ;
    END
  END bank_B_wdata[20]
  PIN bank_B_wdata[21]
    DIRECTION INPUT ;
    USE SIGNAL ;
    ANTENNAGATEAREA 0.180700 ;
    PORT
      LAYER Metal3 ;
        RECT 0.000 113.620 0.400 114.020 ;
    END
  END bank_B_wdata[21]
  PIN bank_B_wdata[22]
    DIRECTION INPUT ;
    USE SIGNAL ;
    ANTENNAGATEAREA 0.180700 ;
    PORT
      LAYER Metal3 ;
        RECT 0.000 116.140 0.400 116.540 ;
    END
  END bank_B_wdata[22]
  PIN bank_B_wdata[23]
    DIRECTION INPUT ;
    USE SIGNAL ;
    ANTENNAGATEAREA 0.180700 ;
    PORT
      LAYER Metal3 ;
        RECT 0.000 118.660 0.400 119.060 ;
    END
  END bank_B_wdata[23]
  PIN bank_B_wdata[24]
    DIRECTION INPUT ;
    USE SIGNAL ;
    ANTENNAGATEAREA 0.180700 ;
    PORT
      LAYER Metal3 ;
        RECT 0.000 121.180 0.400 121.580 ;
    END
  END bank_B_wdata[24]
  PIN bank_B_wdata[25]
    DIRECTION INPUT ;
    USE SIGNAL ;
    ANTENNAGATEAREA 0.180700 ;
    PORT
      LAYER Metal3 ;
        RECT 0.000 123.700 0.400 124.100 ;
    END
  END bank_B_wdata[25]
  PIN bank_B_wdata[26]
    DIRECTION INPUT ;
    USE SIGNAL ;
    ANTENNAGATEAREA 0.180700 ;
    PORT
      LAYER Metal3 ;
        RECT 0.000 126.220 0.400 126.620 ;
    END
  END bank_B_wdata[26]
  PIN bank_B_wdata[27]
    DIRECTION INPUT ;
    USE SIGNAL ;
    ANTENNAGATEAREA 0.180700 ;
    PORT
      LAYER Metal3 ;
        RECT 0.000 128.740 0.400 129.140 ;
    END
  END bank_B_wdata[27]
  PIN bank_B_wdata[28]
    DIRECTION INPUT ;
    USE SIGNAL ;
    ANTENNAGATEAREA 0.180700 ;
    PORT
      LAYER Metal3 ;
        RECT 0.000 131.260 0.400 131.660 ;
    END
  END bank_B_wdata[28]
  PIN bank_B_wdata[29]
    DIRECTION INPUT ;
    USE SIGNAL ;
    ANTENNAGATEAREA 0.180700 ;
    PORT
      LAYER Metal3 ;
        RECT 0.000 133.780 0.400 134.180 ;
    END
  END bank_B_wdata[29]
  PIN bank_B_wdata[2]
    DIRECTION INPUT ;
    USE SIGNAL ;
    ANTENNAGATEAREA 0.180700 ;
    PORT
      LAYER Metal3 ;
        RECT 0.000 65.740 0.400 66.140 ;
    END
  END bank_B_wdata[2]
  PIN bank_B_wdata[30]
    DIRECTION INPUT ;
    USE SIGNAL ;
    ANTENNAGATEAREA 0.180700 ;
    PORT
      LAYER Metal3 ;
        RECT 0.000 136.300 0.400 136.700 ;
    END
  END bank_B_wdata[30]
  PIN bank_B_wdata[31]
    DIRECTION INPUT ;
    USE SIGNAL ;
    ANTENNAGATEAREA 0.180700 ;
    PORT
      LAYER Metal3 ;
        RECT 0.000 138.820 0.400 139.220 ;
    END
  END bank_B_wdata[31]
  PIN bank_B_wdata[3]
    DIRECTION INPUT ;
    USE SIGNAL ;
    ANTENNAGATEAREA 0.180700 ;
    PORT
      LAYER Metal3 ;
        RECT 0.000 68.260 0.400 68.660 ;
    END
  END bank_B_wdata[3]
  PIN bank_B_wdata[4]
    DIRECTION INPUT ;
    USE SIGNAL ;
    ANTENNAGATEAREA 0.180700 ;
    PORT
      LAYER Metal3 ;
        RECT 0.000 70.780 0.400 71.180 ;
    END
  END bank_B_wdata[4]
  PIN bank_B_wdata[5]
    DIRECTION INPUT ;
    USE SIGNAL ;
    ANTENNAGATEAREA 0.180700 ;
    PORT
      LAYER Metal3 ;
        RECT 0.000 73.300 0.400 73.700 ;
    END
  END bank_B_wdata[5]
  PIN bank_B_wdata[6]
    DIRECTION INPUT ;
    USE SIGNAL ;
    ANTENNAGATEAREA 0.180700 ;
    PORT
      LAYER Metal3 ;
        RECT 0.000 75.820 0.400 76.220 ;
    END
  END bank_B_wdata[6]
  PIN bank_B_wdata[7]
    DIRECTION INPUT ;
    USE SIGNAL ;
    ANTENNAGATEAREA 0.180700 ;
    PORT
      LAYER Metal3 ;
        RECT 0.000 78.340 0.400 78.740 ;
    END
  END bank_B_wdata[7]
  PIN bank_B_wdata[8]
    DIRECTION INPUT ;
    USE SIGNAL ;
    ANTENNAGATEAREA 0.180700 ;
    PORT
      LAYER Metal3 ;
        RECT 0.000 80.860 0.400 81.260 ;
    END
  END bank_B_wdata[8]
  PIN bank_B_wdata[9]
    DIRECTION INPUT ;
    USE SIGNAL ;
    ANTENNAGATEAREA 0.180700 ;
    PORT
      LAYER Metal3 ;
        RECT 0.000 83.380 0.400 83.780 ;
    END
  END bank_B_wdata[9]
  PIN bank_B_we
    DIRECTION INPUT ;
    USE SIGNAL ;
    ANTENNAGATEAREA 0.180700 ;
    PORT
      LAYER Metal3 ;
        RECT 0.000 58.180 0.400 58.580 ;
    END
  END bank_B_we
  PIN clk_i
    DIRECTION INPUT ;
    USE SIGNAL ;
    ANTENNAGATEAREA 2.901600 ;
    PORT
      LAYER Metal3 ;
        RECT 0.000 221.980 0.400 222.380 ;
    END
  END clk_i
  PIN psum_lut_en
    DIRECTION INPUT ;
    USE SIGNAL ;
    ANTENNAGATEAREA 0.180700 ;
    PORT
      LAYER Metal3 ;
        RECT 0.000 35.500 0.400 35.900 ;
    END
  END psum_lut_en
  PIN quant_cfg[0]
    DIRECTION INPUT ;
    USE SIGNAL ;
    ANTENNAGATEAREA 0.180700 ;
    PORT
      LAYER Metal3 ;
        RECT 0.000 410.980 0.400 411.380 ;
    END
  END quant_cfg[0]
  PIN quant_cfg[10]
    DIRECTION INPUT ;
    USE SIGNAL ;
    ANTENNAGATEAREA 0.180700 ;
    PORT
      LAYER Metal3 ;
        RECT 0.000 436.180 0.400 436.580 ;
    END
  END quant_cfg[10]
  PIN quant_cfg[11]
    DIRECTION INPUT ;
    USE SIGNAL ;
    ANTENNAGATEAREA 0.180700 ;
    PORT
      LAYER Metal3 ;
        RECT 0.000 438.700 0.400 439.100 ;
    END
  END quant_cfg[11]
  PIN quant_cfg[12]
    DIRECTION INPUT ;
    USE SIGNAL ;
    ANTENNAGATEAREA 0.180700 ;
    PORT
      LAYER Metal3 ;
        RECT 0.000 441.220 0.400 441.620 ;
    END
  END quant_cfg[12]
  PIN quant_cfg[13]
    DIRECTION INPUT ;
    USE SIGNAL ;
    ANTENNAGATEAREA 0.180700 ;
    PORT
      LAYER Metal3 ;
        RECT 0.000 443.740 0.400 444.140 ;
    END
  END quant_cfg[13]
  PIN quant_cfg[14]
    DIRECTION INPUT ;
    USE SIGNAL ;
    ANTENNAGATEAREA 0.180700 ;
    PORT
      LAYER Metal3 ;
        RECT 0.000 446.260 0.400 446.660 ;
    END
  END quant_cfg[14]
  PIN quant_cfg[15]
    DIRECTION INPUT ;
    USE SIGNAL ;
    ANTENNAGATEAREA 0.180700 ;
    PORT
      LAYER Metal3 ;
        RECT 0.000 448.780 0.400 449.180 ;
    END
  END quant_cfg[15]
  PIN quant_cfg[16]
    DIRECTION INPUT ;
    USE SIGNAL ;
    ANTENNAGATEAREA 0.180700 ;
    PORT
      LAYER Metal3 ;
        RECT 0.000 451.300 0.400 451.700 ;
    END
  END quant_cfg[16]
  PIN quant_cfg[17]
    DIRECTION INPUT ;
    USE SIGNAL ;
    ANTENNAGATEAREA 0.180700 ;
    PORT
      LAYER Metal3 ;
        RECT 0.000 453.820 0.400 454.220 ;
    END
  END quant_cfg[17]
  PIN quant_cfg[18]
    DIRECTION INPUT ;
    USE SIGNAL ;
    ANTENNAGATEAREA 0.180700 ;
    PORT
      LAYER Metal3 ;
        RECT 0.000 456.340 0.400 456.740 ;
    END
  END quant_cfg[18]
  PIN quant_cfg[19]
    DIRECTION INPUT ;
    USE SIGNAL ;
    ANTENNAGATEAREA 0.180700 ;
    PORT
      LAYER Metal3 ;
        RECT 0.000 458.860 0.400 459.260 ;
    END
  END quant_cfg[19]
  PIN quant_cfg[1]
    DIRECTION INPUT ;
    USE SIGNAL ;
    ANTENNAGATEAREA 0.180700 ;
    PORT
      LAYER Metal3 ;
        RECT 0.000 413.500 0.400 413.900 ;
    END
  END quant_cfg[1]
  PIN quant_cfg[20]
    DIRECTION INPUT ;
    USE SIGNAL ;
    ANTENNAGATEAREA 0.180700 ;
    PORT
      LAYER Metal3 ;
        RECT 0.000 461.380 0.400 461.780 ;
    END
  END quant_cfg[20]
  PIN quant_cfg[21]
    DIRECTION INPUT ;
    USE SIGNAL ;
    ANTENNAGATEAREA 0.180700 ;
    PORT
      LAYER Metal3 ;
        RECT 0.000 463.900 0.400 464.300 ;
    END
  END quant_cfg[21]
  PIN quant_cfg[22]
    DIRECTION INPUT ;
    USE SIGNAL ;
    ANTENNAGATEAREA 0.180700 ;
    PORT
      LAYER Metal3 ;
        RECT 0.000 466.420 0.400 466.820 ;
    END
  END quant_cfg[22]
  PIN quant_cfg[23]
    DIRECTION INPUT ;
    USE SIGNAL ;
    ANTENNAGATEAREA 0.180700 ;
    PORT
      LAYER Metal3 ;
        RECT 0.000 468.940 0.400 469.340 ;
    END
  END quant_cfg[23]
  PIN quant_cfg[24]
    DIRECTION INPUT ;
    USE SIGNAL ;
    ANTENNAGATEAREA 0.180700 ;
    PORT
      LAYER Metal3 ;
        RECT 0.000 471.460 0.400 471.860 ;
    END
  END quant_cfg[24]
  PIN quant_cfg[25]
    DIRECTION INPUT ;
    USE SIGNAL ;
    ANTENNAGATEAREA 0.180700 ;
    PORT
      LAYER Metal3 ;
        RECT 0.000 473.980 0.400 474.380 ;
    END
  END quant_cfg[25]
  PIN quant_cfg[26]
    DIRECTION INPUT ;
    USE SIGNAL ;
    ANTENNAGATEAREA 0.180700 ;
    PORT
      LAYER Metal3 ;
        RECT 0.000 476.500 0.400 476.900 ;
    END
  END quant_cfg[26]
  PIN quant_cfg[27]
    DIRECTION INPUT ;
    USE SIGNAL ;
    ANTENNAGATEAREA 0.180700 ;
    PORT
      LAYER Metal3 ;
        RECT 0.000 479.020 0.400 479.420 ;
    END
  END quant_cfg[27]
  PIN quant_cfg[28]
    DIRECTION INPUT ;
    USE SIGNAL ;
    ANTENNAGATEAREA 0.180700 ;
    PORT
      LAYER Metal3 ;
        RECT 0.000 481.540 0.400 481.940 ;
    END
  END quant_cfg[28]
  PIN quant_cfg[29]
    DIRECTION INPUT ;
    USE SIGNAL ;
    ANTENNAGATEAREA 0.180700 ;
    PORT
      LAYER Metal3 ;
        RECT 0.000 484.060 0.400 484.460 ;
    END
  END quant_cfg[29]
  PIN quant_cfg[2]
    DIRECTION INPUT ;
    USE SIGNAL ;
    ANTENNAGATEAREA 0.180700 ;
    PORT
      LAYER Metal3 ;
        RECT 0.000 416.020 0.400 416.420 ;
    END
  END quant_cfg[2]
  PIN quant_cfg[3]
    DIRECTION INPUT ;
    USE SIGNAL ;
    ANTENNAGATEAREA 0.180700 ;
    PORT
      LAYER Metal3 ;
        RECT 0.000 418.540 0.400 418.940 ;
    END
  END quant_cfg[3]
  PIN quant_cfg[4]
    DIRECTION INPUT ;
    USE SIGNAL ;
    ANTENNAGATEAREA 0.180700 ;
    PORT
      LAYER Metal3 ;
        RECT 0.000 421.060 0.400 421.460 ;
    END
  END quant_cfg[4]
  PIN quant_cfg[5]
    DIRECTION INPUT ;
    USE SIGNAL ;
    ANTENNAGATEAREA 0.180700 ;
    PORT
      LAYER Metal3 ;
        RECT 0.000 423.580 0.400 423.980 ;
    END
  END quant_cfg[5]
  PIN quant_cfg[6]
    DIRECTION INPUT ;
    USE SIGNAL ;
    ANTENNAGATEAREA 0.180700 ;
    PORT
      LAYER Metal3 ;
        RECT 0.000 426.100 0.400 426.500 ;
    END
  END quant_cfg[6]
  PIN quant_cfg[7]
    DIRECTION INPUT ;
    USE SIGNAL ;
    ANTENNAGATEAREA 0.180700 ;
    PORT
      LAYER Metal3 ;
        RECT 0.000 428.620 0.400 429.020 ;
    END
  END quant_cfg[7]
  PIN quant_cfg[8]
    DIRECTION INPUT ;
    USE SIGNAL ;
    ANTENNAGATEAREA 0.180700 ;
    PORT
      LAYER Metal3 ;
        RECT 0.000 431.140 0.400 431.540 ;
    END
  END quant_cfg[8]
  PIN quant_cfg[9]
    DIRECTION INPUT ;
    USE SIGNAL ;
    ANTENNAGATEAREA 0.180700 ;
    PORT
      LAYER Metal3 ;
        RECT 0.000 433.660 0.400 434.060 ;
    END
  END quant_cfg[9]
  PIN rst_n
    DIRECTION INPUT ;
    USE SIGNAL ;
    ANTENNAGATEAREA 0.180700 ;
    PORT
      LAYER Metal3 ;
        RECT 0.000 224.500 0.400 224.900 ;
    END
  END rst_n
  OBS
      LAYER GatPoly ;
        RECT 9.600 11.190 450.240 487.770 ;
      LAYER Metal1 ;
        RECT 9.600 11.120 450.240 487.840 ;
      LAYER Metal2 ;
        RECT 0.375 11.195 448.905 487.765 ;
      LAYER Metal3 ;
        RECT 0.100 484.670 448.945 487.720 ;
        RECT 0.610 483.850 448.945 484.670 ;
        RECT 0.100 482.150 448.945 483.850 ;
        RECT 0.610 481.330 448.945 482.150 ;
        RECT 0.100 479.630 448.945 481.330 ;
        RECT 0.610 478.810 448.945 479.630 ;
        RECT 0.100 477.110 448.945 478.810 ;
        RECT 0.610 476.290 448.945 477.110 ;
        RECT 0.100 474.590 448.945 476.290 ;
        RECT 0.610 473.770 448.945 474.590 ;
        RECT 0.100 472.070 448.945 473.770 ;
        RECT 0.610 471.250 448.945 472.070 ;
        RECT 0.100 469.550 448.945 471.250 ;
        RECT 0.610 468.730 448.945 469.550 ;
        RECT 0.100 467.030 448.945 468.730 ;
        RECT 0.610 466.210 448.945 467.030 ;
        RECT 0.100 464.510 448.945 466.210 ;
        RECT 0.610 463.690 448.945 464.510 ;
        RECT 0.100 461.990 448.945 463.690 ;
        RECT 0.610 461.170 448.945 461.990 ;
        RECT 0.100 459.470 448.945 461.170 ;
        RECT 0.610 458.650 448.945 459.470 ;
        RECT 0.100 456.950 448.945 458.650 ;
        RECT 0.610 456.130 448.945 456.950 ;
        RECT 0.100 454.430 448.945 456.130 ;
        RECT 0.610 453.610 448.945 454.430 ;
        RECT 0.100 451.910 448.945 453.610 ;
        RECT 0.610 451.090 448.945 451.910 ;
        RECT 0.100 449.390 448.945 451.090 ;
        RECT 0.610 448.570 448.945 449.390 ;
        RECT 0.100 446.870 448.945 448.570 ;
        RECT 0.610 446.050 448.945 446.870 ;
        RECT 0.100 444.350 448.945 446.050 ;
        RECT 0.610 443.530 448.945 444.350 ;
        RECT 0.100 441.830 448.945 443.530 ;
        RECT 0.610 441.010 448.945 441.830 ;
        RECT 0.100 439.310 448.945 441.010 ;
        RECT 0.610 438.490 448.945 439.310 ;
        RECT 0.100 436.790 448.945 438.490 ;
        RECT 0.610 435.970 448.945 436.790 ;
        RECT 0.100 434.270 448.945 435.970 ;
        RECT 0.610 433.450 448.945 434.270 ;
        RECT 0.100 431.750 448.945 433.450 ;
        RECT 0.610 430.930 448.945 431.750 ;
        RECT 0.100 429.230 448.945 430.930 ;
        RECT 0.610 428.410 448.945 429.230 ;
        RECT 0.100 426.710 448.945 428.410 ;
        RECT 0.610 425.890 448.945 426.710 ;
        RECT 0.100 424.190 448.945 425.890 ;
        RECT 0.610 423.370 448.945 424.190 ;
        RECT 0.100 421.670 448.945 423.370 ;
        RECT 0.610 420.850 448.945 421.670 ;
        RECT 0.100 419.150 448.945 420.850 ;
        RECT 0.610 418.330 448.945 419.150 ;
        RECT 0.100 416.630 448.945 418.330 ;
        RECT 0.610 415.810 448.945 416.630 ;
        RECT 0.100 414.110 448.945 415.810 ;
        RECT 0.610 413.290 448.945 414.110 ;
        RECT 0.100 411.590 448.945 413.290 ;
        RECT 0.610 410.770 448.945 411.590 ;
        RECT 0.100 409.070 448.945 410.770 ;
        RECT 0.610 408.250 448.945 409.070 ;
        RECT 0.100 406.550 448.945 408.250 ;
        RECT 0.610 405.730 448.945 406.550 ;
        RECT 0.100 404.030 448.945 405.730 ;
        RECT 0.610 403.210 448.945 404.030 ;
        RECT 0.100 401.510 448.945 403.210 ;
        RECT 0.610 400.690 448.945 401.510 ;
        RECT 0.100 398.990 448.945 400.690 ;
        RECT 0.610 398.170 448.945 398.990 ;
        RECT 0.100 396.470 448.945 398.170 ;
        RECT 0.610 395.650 448.945 396.470 ;
        RECT 0.100 393.950 448.945 395.650 ;
        RECT 0.610 393.130 448.945 393.950 ;
        RECT 0.100 391.430 448.945 393.130 ;
        RECT 0.610 390.610 448.945 391.430 ;
        RECT 0.100 388.910 448.945 390.610 ;
        RECT 0.610 388.090 448.945 388.910 ;
        RECT 0.100 386.390 448.945 388.090 ;
        RECT 0.610 385.570 448.945 386.390 ;
        RECT 0.100 383.870 448.945 385.570 ;
        RECT 0.610 383.050 448.945 383.870 ;
        RECT 0.100 381.350 448.945 383.050 ;
        RECT 0.610 380.530 448.945 381.350 ;
        RECT 0.100 378.830 448.945 380.530 ;
        RECT 0.610 378.010 448.945 378.830 ;
        RECT 0.100 376.310 448.945 378.010 ;
        RECT 0.610 375.490 448.945 376.310 ;
        RECT 0.100 373.790 448.945 375.490 ;
        RECT 0.610 372.970 448.945 373.790 ;
        RECT 0.100 371.270 448.945 372.970 ;
        RECT 0.610 370.450 448.945 371.270 ;
        RECT 0.100 368.750 448.945 370.450 ;
        RECT 0.610 367.930 448.945 368.750 ;
        RECT 0.100 366.230 448.945 367.930 ;
        RECT 0.610 365.410 448.945 366.230 ;
        RECT 0.100 363.710 448.945 365.410 ;
        RECT 0.610 362.890 448.945 363.710 ;
        RECT 0.100 361.190 448.945 362.890 ;
        RECT 0.610 360.370 448.945 361.190 ;
        RECT 0.100 358.670 448.945 360.370 ;
        RECT 0.610 357.850 448.945 358.670 ;
        RECT 0.100 356.150 448.945 357.850 ;
        RECT 0.610 355.330 448.945 356.150 ;
        RECT 0.100 353.630 448.945 355.330 ;
        RECT 0.610 352.810 448.945 353.630 ;
        RECT 0.100 351.110 448.945 352.810 ;
        RECT 0.610 350.290 448.945 351.110 ;
        RECT 0.100 348.590 448.945 350.290 ;
        RECT 0.610 347.770 448.945 348.590 ;
        RECT 0.100 346.070 448.945 347.770 ;
        RECT 0.610 345.250 448.945 346.070 ;
        RECT 0.100 343.550 448.945 345.250 ;
        RECT 0.610 342.730 448.945 343.550 ;
        RECT 0.100 341.030 448.945 342.730 ;
        RECT 0.610 340.210 448.945 341.030 ;
        RECT 0.100 338.510 448.945 340.210 ;
        RECT 0.610 337.690 448.945 338.510 ;
        RECT 0.100 335.990 448.945 337.690 ;
        RECT 0.610 335.170 448.945 335.990 ;
        RECT 0.100 333.470 448.945 335.170 ;
        RECT 0.610 332.650 448.945 333.470 ;
        RECT 0.100 330.950 448.945 332.650 ;
        RECT 0.610 330.130 448.945 330.950 ;
        RECT 0.100 328.430 448.945 330.130 ;
        RECT 0.610 327.610 448.945 328.430 ;
        RECT 0.100 325.910 448.945 327.610 ;
        RECT 0.610 325.090 448.945 325.910 ;
        RECT 0.100 323.390 448.945 325.090 ;
        RECT 0.610 322.570 448.945 323.390 ;
        RECT 0.100 320.870 448.945 322.570 ;
        RECT 0.610 320.050 448.945 320.870 ;
        RECT 0.100 318.350 448.945 320.050 ;
        RECT 0.610 317.530 448.945 318.350 ;
        RECT 0.100 315.830 448.945 317.530 ;
        RECT 0.610 315.010 448.945 315.830 ;
        RECT 0.100 313.310 448.945 315.010 ;
        RECT 0.610 312.490 448.945 313.310 ;
        RECT 0.100 310.790 448.945 312.490 ;
        RECT 0.610 309.970 448.945 310.790 ;
        RECT 0.100 308.270 448.945 309.970 ;
        RECT 0.610 307.450 448.945 308.270 ;
        RECT 0.100 305.750 448.945 307.450 ;
        RECT 0.610 304.930 448.945 305.750 ;
        RECT 0.100 303.230 448.945 304.930 ;
        RECT 0.610 302.410 448.945 303.230 ;
        RECT 0.100 300.710 448.945 302.410 ;
        RECT 0.610 299.890 448.945 300.710 ;
        RECT 0.100 298.190 448.945 299.890 ;
        RECT 0.610 297.370 448.945 298.190 ;
        RECT 0.100 295.670 448.945 297.370 ;
        RECT 0.610 294.850 448.945 295.670 ;
        RECT 0.100 293.150 448.945 294.850 ;
        RECT 0.610 292.330 448.945 293.150 ;
        RECT 0.100 290.630 448.945 292.330 ;
        RECT 0.610 289.810 448.945 290.630 ;
        RECT 0.100 288.110 448.945 289.810 ;
        RECT 0.610 287.290 448.945 288.110 ;
        RECT 0.100 285.590 448.945 287.290 ;
        RECT 0.610 284.770 448.945 285.590 ;
        RECT 0.100 283.070 448.945 284.770 ;
        RECT 0.610 282.250 448.945 283.070 ;
        RECT 0.100 280.550 448.945 282.250 ;
        RECT 0.610 279.730 448.945 280.550 ;
        RECT 0.100 278.030 448.945 279.730 ;
        RECT 0.610 277.210 448.945 278.030 ;
        RECT 0.100 275.510 448.945 277.210 ;
        RECT 0.610 274.690 448.945 275.510 ;
        RECT 0.100 272.990 448.945 274.690 ;
        RECT 0.610 272.170 448.945 272.990 ;
        RECT 0.100 270.470 448.945 272.170 ;
        RECT 0.610 269.650 448.945 270.470 ;
        RECT 0.100 267.950 448.945 269.650 ;
        RECT 0.610 267.130 448.945 267.950 ;
        RECT 0.100 265.430 448.945 267.130 ;
        RECT 0.610 264.610 448.945 265.430 ;
        RECT 0.100 262.910 448.945 264.610 ;
        RECT 0.610 262.090 448.945 262.910 ;
        RECT 0.100 260.390 448.945 262.090 ;
        RECT 0.610 259.570 448.945 260.390 ;
        RECT 0.100 257.870 448.945 259.570 ;
        RECT 0.610 257.050 448.945 257.870 ;
        RECT 0.100 255.350 448.945 257.050 ;
        RECT 0.610 254.530 448.945 255.350 ;
        RECT 0.100 252.830 448.945 254.530 ;
        RECT 0.610 252.010 448.945 252.830 ;
        RECT 0.100 250.310 448.945 252.010 ;
        RECT 0.610 249.490 448.945 250.310 ;
        RECT 0.100 247.790 448.945 249.490 ;
        RECT 0.610 246.970 448.945 247.790 ;
        RECT 0.100 245.270 448.945 246.970 ;
        RECT 0.610 244.450 448.945 245.270 ;
        RECT 0.100 242.750 448.945 244.450 ;
        RECT 0.610 241.930 448.945 242.750 ;
        RECT 0.100 240.230 448.945 241.930 ;
        RECT 0.610 239.410 448.945 240.230 ;
        RECT 0.100 237.710 448.945 239.410 ;
        RECT 0.610 236.890 448.945 237.710 ;
        RECT 0.100 235.190 448.945 236.890 ;
        RECT 0.610 234.370 448.945 235.190 ;
        RECT 0.100 232.670 448.945 234.370 ;
        RECT 0.610 231.850 448.945 232.670 ;
        RECT 0.100 230.150 448.945 231.850 ;
        RECT 0.610 229.330 448.945 230.150 ;
        RECT 0.100 227.630 448.945 229.330 ;
        RECT 0.610 226.810 448.945 227.630 ;
        RECT 0.100 225.110 448.945 226.810 ;
        RECT 0.610 224.290 448.945 225.110 ;
        RECT 0.100 222.590 448.945 224.290 ;
        RECT 0.610 221.770 448.945 222.590 ;
        RECT 0.100 220.070 448.945 221.770 ;
        RECT 0.610 219.250 448.945 220.070 ;
        RECT 0.100 217.550 448.945 219.250 ;
        RECT 0.610 216.730 448.945 217.550 ;
        RECT 0.100 215.030 448.945 216.730 ;
        RECT 0.610 214.210 448.945 215.030 ;
        RECT 0.100 212.510 448.945 214.210 ;
        RECT 0.610 211.690 448.945 212.510 ;
        RECT 0.100 209.990 448.945 211.690 ;
        RECT 0.610 209.170 448.945 209.990 ;
        RECT 0.100 207.470 448.945 209.170 ;
        RECT 0.610 206.650 448.945 207.470 ;
        RECT 0.100 204.950 448.945 206.650 ;
        RECT 0.610 204.130 448.945 204.950 ;
        RECT 0.100 202.430 448.945 204.130 ;
        RECT 0.610 201.610 448.945 202.430 ;
        RECT 0.100 199.910 448.945 201.610 ;
        RECT 0.610 199.090 448.945 199.910 ;
        RECT 0.100 197.390 448.945 199.090 ;
        RECT 0.610 196.570 448.945 197.390 ;
        RECT 0.100 194.870 448.945 196.570 ;
        RECT 0.610 194.050 448.945 194.870 ;
        RECT 0.100 192.350 448.945 194.050 ;
        RECT 0.610 191.530 448.945 192.350 ;
        RECT 0.100 189.830 448.945 191.530 ;
        RECT 0.610 189.010 448.945 189.830 ;
        RECT 0.100 187.310 448.945 189.010 ;
        RECT 0.610 186.490 448.945 187.310 ;
        RECT 0.100 184.790 448.945 186.490 ;
        RECT 0.610 183.970 448.945 184.790 ;
        RECT 0.100 182.270 448.945 183.970 ;
        RECT 0.610 181.450 448.945 182.270 ;
        RECT 0.100 179.750 448.945 181.450 ;
        RECT 0.610 178.930 448.945 179.750 ;
        RECT 0.100 177.230 448.945 178.930 ;
        RECT 0.610 176.410 448.945 177.230 ;
        RECT 0.100 174.710 448.945 176.410 ;
        RECT 0.610 173.890 448.945 174.710 ;
        RECT 0.100 172.190 448.945 173.890 ;
        RECT 0.610 171.370 448.945 172.190 ;
        RECT 0.100 169.670 448.945 171.370 ;
        RECT 0.610 168.850 448.945 169.670 ;
        RECT 0.100 167.150 448.945 168.850 ;
        RECT 0.610 166.330 448.945 167.150 ;
        RECT 0.100 164.630 448.945 166.330 ;
        RECT 0.610 163.810 448.945 164.630 ;
        RECT 0.100 162.110 448.945 163.810 ;
        RECT 0.610 161.290 448.945 162.110 ;
        RECT 0.100 159.590 448.945 161.290 ;
        RECT 0.610 158.770 448.945 159.590 ;
        RECT 0.100 157.070 448.945 158.770 ;
        RECT 0.610 156.250 448.945 157.070 ;
        RECT 0.100 154.550 448.945 156.250 ;
        RECT 0.610 153.730 448.945 154.550 ;
        RECT 0.100 152.030 448.945 153.730 ;
        RECT 0.610 151.210 448.945 152.030 ;
        RECT 0.100 149.510 448.945 151.210 ;
        RECT 0.610 148.690 448.945 149.510 ;
        RECT 0.100 146.990 448.945 148.690 ;
        RECT 0.610 146.170 448.945 146.990 ;
        RECT 0.100 144.470 448.945 146.170 ;
        RECT 0.610 143.650 448.945 144.470 ;
        RECT 0.100 141.950 448.945 143.650 ;
        RECT 0.610 141.130 448.945 141.950 ;
        RECT 0.100 139.430 448.945 141.130 ;
        RECT 0.610 138.610 448.945 139.430 ;
        RECT 0.100 136.910 448.945 138.610 ;
        RECT 0.610 136.090 448.945 136.910 ;
        RECT 0.100 134.390 448.945 136.090 ;
        RECT 0.610 133.570 448.945 134.390 ;
        RECT 0.100 131.870 448.945 133.570 ;
        RECT 0.610 131.050 448.945 131.870 ;
        RECT 0.100 129.350 448.945 131.050 ;
        RECT 0.610 128.530 448.945 129.350 ;
        RECT 0.100 126.830 448.945 128.530 ;
        RECT 0.610 126.010 448.945 126.830 ;
        RECT 0.100 124.310 448.945 126.010 ;
        RECT 0.610 123.490 448.945 124.310 ;
        RECT 0.100 121.790 448.945 123.490 ;
        RECT 0.610 120.970 448.945 121.790 ;
        RECT 0.100 119.270 448.945 120.970 ;
        RECT 0.610 118.450 448.945 119.270 ;
        RECT 0.100 116.750 448.945 118.450 ;
        RECT 0.610 115.930 448.945 116.750 ;
        RECT 0.100 114.230 448.945 115.930 ;
        RECT 0.610 113.410 448.945 114.230 ;
        RECT 0.100 111.710 448.945 113.410 ;
        RECT 0.610 110.890 448.945 111.710 ;
        RECT 0.100 109.190 448.945 110.890 ;
        RECT 0.610 108.370 448.945 109.190 ;
        RECT 0.100 106.670 448.945 108.370 ;
        RECT 0.610 105.850 448.945 106.670 ;
        RECT 0.100 104.150 448.945 105.850 ;
        RECT 0.610 103.330 448.945 104.150 ;
        RECT 0.100 101.630 448.945 103.330 ;
        RECT 0.610 100.810 448.945 101.630 ;
        RECT 0.100 99.110 448.945 100.810 ;
        RECT 0.610 98.290 448.945 99.110 ;
        RECT 0.100 96.590 448.945 98.290 ;
        RECT 0.610 95.770 448.945 96.590 ;
        RECT 0.100 94.070 448.945 95.770 ;
        RECT 0.610 93.250 448.945 94.070 ;
        RECT 0.100 91.550 448.945 93.250 ;
        RECT 0.610 90.730 448.945 91.550 ;
        RECT 0.100 89.030 448.945 90.730 ;
        RECT 0.610 88.210 448.945 89.030 ;
        RECT 0.100 86.510 448.945 88.210 ;
        RECT 0.610 85.690 448.945 86.510 ;
        RECT 0.100 83.990 448.945 85.690 ;
        RECT 0.610 83.170 448.945 83.990 ;
        RECT 0.100 81.470 448.945 83.170 ;
        RECT 0.610 80.650 448.945 81.470 ;
        RECT 0.100 78.950 448.945 80.650 ;
        RECT 0.610 78.130 448.945 78.950 ;
        RECT 0.100 76.430 448.945 78.130 ;
        RECT 0.610 75.610 448.945 76.430 ;
        RECT 0.100 73.910 448.945 75.610 ;
        RECT 0.610 73.090 448.945 73.910 ;
        RECT 0.100 71.390 448.945 73.090 ;
        RECT 0.610 70.570 448.945 71.390 ;
        RECT 0.100 68.870 448.945 70.570 ;
        RECT 0.610 68.050 448.945 68.870 ;
        RECT 0.100 66.350 448.945 68.050 ;
        RECT 0.610 65.530 448.945 66.350 ;
        RECT 0.100 63.830 448.945 65.530 ;
        RECT 0.610 63.010 448.945 63.830 ;
        RECT 0.100 61.310 448.945 63.010 ;
        RECT 0.610 60.490 448.945 61.310 ;
        RECT 0.100 58.790 448.945 60.490 ;
        RECT 0.610 57.970 448.945 58.790 ;
        RECT 0.100 56.270 448.945 57.970 ;
        RECT 0.610 55.450 448.945 56.270 ;
        RECT 0.100 53.750 448.945 55.450 ;
        RECT 0.610 52.930 448.945 53.750 ;
        RECT 0.100 51.230 448.945 52.930 ;
        RECT 0.610 50.410 448.945 51.230 ;
        RECT 0.100 48.710 448.945 50.410 ;
        RECT 0.610 47.890 448.945 48.710 ;
        RECT 0.100 46.190 448.945 47.890 ;
        RECT 0.610 45.370 448.945 46.190 ;
        RECT 0.100 43.670 448.945 45.370 ;
        RECT 0.610 42.850 448.945 43.670 ;
        RECT 0.100 41.150 448.945 42.850 ;
        RECT 0.610 40.330 448.945 41.150 ;
        RECT 0.100 38.630 448.945 40.330 ;
        RECT 0.610 37.810 448.945 38.630 ;
        RECT 0.100 36.110 448.945 37.810 ;
        RECT 0.610 35.290 448.945 36.110 ;
        RECT 0.100 33.590 448.945 35.290 ;
        RECT 0.610 32.770 448.945 33.590 ;
        RECT 0.100 31.070 448.945 32.770 ;
        RECT 0.610 30.250 448.945 31.070 ;
        RECT 0.100 28.550 448.945 30.250 ;
        RECT 0.610 27.730 448.945 28.550 ;
        RECT 0.100 26.030 448.945 27.730 ;
        RECT 0.610 25.210 448.945 26.030 ;
        RECT 0.100 23.510 448.945 25.210 ;
        RECT 0.610 22.690 448.945 23.510 ;
        RECT 0.100 20.990 448.945 22.690 ;
        RECT 0.610 20.170 448.945 20.990 ;
        RECT 0.100 18.470 448.945 20.170 ;
        RECT 0.610 17.650 448.945 18.470 ;
        RECT 0.100 15.950 448.945 17.650 ;
        RECT 0.610 15.130 448.945 15.950 ;
        RECT 0.100 11.240 448.945 15.130 ;
      LAYER Metal4 ;
        RECT 0.860 343.550 13.690 478.780 ;
        RECT 15.110 343.550 18.890 478.780 ;
        RECT 0.860 155.410 18.890 343.550 ;
        RECT 0.860 14.135 13.690 155.410 ;
        RECT 15.110 14.135 18.890 155.410 ;
        RECT 20.310 14.135 21.890 478.780 ;
        RECT 23.310 357.970 442.390 478.780 ;
        RECT 23.310 357.730 71.890 357.970 ;
        RECT 23.310 141.050 68.890 357.730 ;
        RECT 70.310 141.050 71.890 357.730 ;
        RECT 23.310 140.810 71.890 141.050 ;
        RECT 73.310 357.730 121.890 357.970 ;
        RECT 73.310 141.050 118.890 357.730 ;
        RECT 120.310 141.050 121.890 357.730 ;
        RECT 73.310 140.810 121.890 141.050 ;
        RECT 123.310 357.730 268.890 357.970 ;
        RECT 123.310 141.050 168.890 357.730 ;
        RECT 170.310 141.050 171.890 357.730 ;
        RECT 173.310 141.050 218.890 357.730 ;
        RECT 220.310 141.050 221.890 357.730 ;
        RECT 223.310 141.050 268.890 357.730 ;
        RECT 123.310 140.810 268.890 141.050 ;
        RECT 270.310 357.730 442.390 357.970 ;
        RECT 270.310 141.050 271.890 357.730 ;
        RECT 273.310 141.050 318.890 357.730 ;
        RECT 320.310 141.050 321.890 357.730 ;
        RECT 323.310 141.050 368.890 357.730 ;
        RECT 370.310 141.050 371.890 357.730 ;
        RECT 373.310 141.050 418.890 357.730 ;
        RECT 420.310 141.050 421.890 357.730 ;
        RECT 423.310 141.050 442.390 357.730 ;
        RECT 270.310 140.810 442.390 141.050 ;
        RECT 23.310 17.970 442.390 140.810 ;
        RECT 23.310 17.730 268.890 17.970 ;
        RECT 23.310 14.135 68.890 17.730 ;
        RECT 70.310 14.135 118.890 17.730 ;
        RECT 120.310 14.135 168.890 17.730 ;
        RECT 170.310 14.135 218.890 17.730 ;
        RECT 220.310 14.135 268.890 17.730 ;
        RECT 270.310 17.730 442.390 17.970 ;
        RECT 270.310 14.135 318.890 17.730 ;
        RECT 320.310 14.135 368.890 17.730 ;
        RECT 370.310 14.135 418.890 17.730 ;
        RECT 420.310 14.135 442.390 17.730 ;
      LAYER TopMetal1 ;
        RECT 2.060 347.090 442.900 374.100 ;
        RECT 2.060 341.090 442.900 341.810 ;
        RECT 2.060 301.060 442.900 335.810 ;
        RECT 2.060 295.060 442.900 295.780 ;
        RECT 2.060 255.030 442.900 289.780 ;
        RECT 2.060 249.030 442.900 249.750 ;
        RECT 2.060 209.000 442.900 243.750 ;
        RECT 2.060 203.000 442.900 203.720 ;
        RECT 2.060 162.970 442.900 197.720 ;
        RECT 2.060 156.970 442.900 157.690 ;
        RECT 2.060 139.900 442.900 151.690 ;
  END
END psum_requant_container
END LIBRARY

